VERSION 5.8 ;
BUSBITCHARS "[]" ;
DIVIDERCHAR "/" ;
UNITS
    DATABASE MICRONS 1000 ;
END UNITS

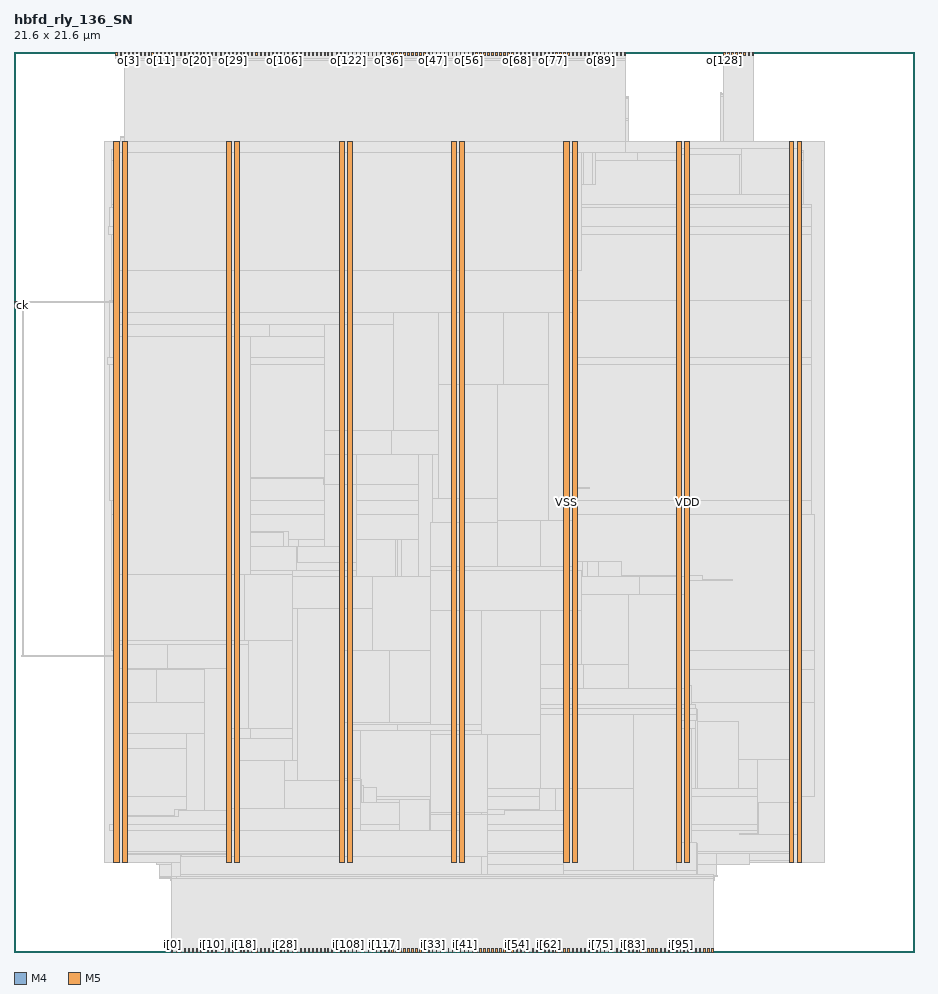
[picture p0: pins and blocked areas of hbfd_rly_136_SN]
MACRO hbfd_rly_136_SN
  FOREIGN hbfd_rly_136_SN 0 0 ;
  CLASS BLOCK ;
  SIZE 21.6 BY 21.6 ;
  PIN ck
    DIRECTION INPUT ;
    USE SIGNAL ;
    PORT
      LAYER M4 ;
        RECT  0 15.504 0.084 15.528 ;
    END
  END ck
  PIN i[0]
    DIRECTION INPUT ;
    USE SIGNAL ;
    PORT
      LAYER M5 ;
        RECT  3.792 0 3.816 0.084 ;
    END
  END i[0]
  PIN i[100]
    DIRECTION INPUT ;
    USE SIGNAL ;
    PORT
      LAYER M5 ;
        RECT  7.248 0 7.272 0.084 ;
    END
  END i[100]
  PIN i[101]
    DIRECTION INPUT ;
    USE SIGNAL ;
    PORT
      LAYER M5 ;
        RECT  7.344 0 7.368 0.084 ;
    END
  END i[101]
  PIN i[102]
    DIRECTION INPUT ;
    USE SIGNAL ;
    PORT
      LAYER M5 ;
        RECT  7.44 0 7.464 0.084 ;
    END
  END i[102]
  PIN i[103]
    DIRECTION INPUT ;
    USE SIGNAL ;
    PORT
      LAYER M5 ;
        RECT  7.536 0 7.56 0.084 ;
    END
  END i[103]
  PIN i[104]
    DIRECTION INPUT ;
    USE SIGNAL ;
    PORT
      LAYER M5 ;
        RECT  7.632 0 7.656 0.084 ;
    END
  END i[104]
  PIN i[105]
    DIRECTION INPUT ;
    USE SIGNAL ;
    PORT
      LAYER M5 ;
        RECT  7.728 0 7.752 0.084 ;
    END
  END i[105]
  PIN i[106]
    DIRECTION INPUT ;
    USE SIGNAL ;
    PORT
      LAYER M5 ;
        RECT  7.824 0 7.848 0.084 ;
    END
  END i[106]
  PIN i[107]
    DIRECTION INPUT ;
    USE SIGNAL ;
    PORT
      LAYER M5 ;
        RECT  7.92 0 7.944 0.084 ;
    END
  END i[107]
  PIN i[108]
    DIRECTION INPUT ;
    USE SIGNAL ;
    PORT
      LAYER M5 ;
        RECT  8.016 0 8.04 0.084 ;
    END
  END i[108]
  PIN i[109]
    DIRECTION INPUT ;
    USE SIGNAL ;
    PORT
      LAYER M5 ;
        RECT  8.112 0 8.136 0.084 ;
    END
  END i[109]
  PIN i[10]
    DIRECTION INPUT ;
    USE SIGNAL ;
    PORT
      LAYER M5 ;
        RECT  4.752 0 4.776 0.084 ;
    END
  END i[10]
  PIN i[110]
    DIRECTION INPUT ;
    USE SIGNAL ;
    PORT
      LAYER M5 ;
        RECT  8.208 0 8.232 0.084 ;
    END
  END i[110]
  PIN i[111]
    DIRECTION INPUT ;
    USE SIGNAL ;
    PORT
      LAYER M5 ;
        RECT  8.304 0 8.328 0.084 ;
    END
  END i[111]
  PIN i[112]
    DIRECTION INPUT ;
    USE SIGNAL ;
    PORT
      LAYER M5 ;
        RECT  8.4 0 8.424 0.084 ;
    END
  END i[112]
  PIN i[113]
    DIRECTION INPUT ;
    USE SIGNAL ;
    PORT
      LAYER M5 ;
        RECT  8.496 0 8.52 0.084 ;
    END
  END i[113]
  PIN i[114]
    DIRECTION INPUT ;
    USE SIGNAL ;
    PORT
      LAYER M5 ;
        RECT  8.592 0 8.616 0.084 ;
    END
  END i[114]
  PIN i[115]
    DIRECTION INPUT ;
    USE SIGNAL ;
    PORT
      LAYER M5 ;
        RECT  8.688 0 8.712 0.084 ;
    END
  END i[115]
  PIN i[116]
    DIRECTION INPUT ;
    USE SIGNAL ;
    PORT
      LAYER M5 ;
        RECT  8.784 0 8.808 0.084 ;
    END
  END i[116]
  PIN i[117]
    DIRECTION INPUT ;
    USE SIGNAL ;
    PORT
      LAYER M5 ;
        RECT  8.88 0 8.904 0.084 ;
    END
  END i[117]
  PIN i[118]
    DIRECTION INPUT ;
    USE SIGNAL ;
    PORT
      LAYER M5 ;
        RECT  8.976 0 9 0.084 ;
    END
  END i[118]
  PIN i[119]
    DIRECTION INPUT ;
    USE SIGNAL ;
    PORT
      LAYER M5 ;
        RECT  9.072 0 9.096 0.084 ;
    END
  END i[119]
  PIN i[11]
    DIRECTION INPUT ;
    USE SIGNAL ;
    PORT
      LAYER M5 ;
        RECT  4.848 0 4.872 0.084 ;
    END
  END i[11]
  PIN i[120]
    DIRECTION INPUT ;
    USE SIGNAL ;
    PORT
      LAYER M5 ;
        RECT  9.168 0 9.192 0.084 ;
    END
  END i[120]
  PIN i[121]
    DIRECTION INPUT ;
    USE SIGNAL ;
    PORT
      LAYER M5 ;
        RECT  9.264 0 9.288 0.084 ;
    END
  END i[121]
  PIN i[122]
    DIRECTION INPUT ;
    USE SIGNAL ;
    PORT
      LAYER M5 ;
        RECT  9.36 0 9.384 0.084 ;
    END
  END i[122]
  PIN i[123]
    DIRECTION INPUT ;
    USE SIGNAL ;
    PORT
      LAYER M5 ;
        RECT  9.456 0 9.48 0.084 ;
    END
  END i[123]
  PIN i[124]
    DIRECTION INPUT ;
    USE SIGNAL ;
    PORT
      LAYER M5 ;
        RECT  9.552 0 9.576 0.084 ;
    END
  END i[124]
  PIN i[125]
    DIRECTION INPUT ;
    USE SIGNAL ;
    PORT
      LAYER M5 ;
        RECT  9.648 0 9.672 0.084 ;
    END
  END i[125]
  PIN i[126]
    DIRECTION INPUT ;
    USE SIGNAL ;
    PORT
      LAYER M5 ;
        RECT  9.744 0 9.768 0.084 ;
    END
  END i[126]
  PIN i[127]
    DIRECTION INPUT ;
    USE SIGNAL ;
    PORT
      LAYER M5 ;
        RECT  9.84 0 9.864 0.084 ;
    END
  END i[127]
  PIN i[128]
    DIRECTION INPUT ;
    USE SIGNAL ;
    PORT
      LAYER M5 ;
        RECT  16.08 0 16.104 0.084 ;
    END
  END i[128]
  PIN i[129]
    DIRECTION INPUT ;
    USE SIGNAL ;
    PORT
      LAYER M5 ;
        RECT  16.176 0 16.2 0.084 ;
    END
  END i[129]
  PIN i[12]
    DIRECTION INPUT ;
    USE SIGNAL ;
    PORT
      LAYER M5 ;
        RECT  4.944 0 4.968 0.084 ;
    END
  END i[12]
  PIN i[130]
    DIRECTION INPUT ;
    USE SIGNAL ;
    PORT
      LAYER M5 ;
        RECT  16.272 0 16.296 0.084 ;
    END
  END i[130]
  PIN i[131]
    DIRECTION INPUT ;
    USE SIGNAL ;
    PORT
      LAYER M5 ;
        RECT  16.368 0 16.392 0.084 ;
    END
  END i[131]
  PIN i[132]
    DIRECTION INPUT ;
    USE SIGNAL ;
    PORT
      LAYER M5 ;
        RECT  16.464 0 16.488 0.084 ;
    END
  END i[132]
  PIN i[133]
    DIRECTION INPUT ;
    USE SIGNAL ;
    PORT
      LAYER M5 ;
        RECT  16.56 0 16.584 0.084 ;
    END
  END i[133]
  PIN i[134]
    DIRECTION INPUT ;
    USE SIGNAL ;
    PORT
      LAYER M5 ;
        RECT  16.656 0 16.68 0.084 ;
    END
  END i[134]
  PIN i[135]
    DIRECTION INPUT ;
    USE SIGNAL ;
    PORT
      LAYER M5 ;
        RECT  16.752 0 16.776 0.084 ;
    END
  END i[135]
  PIN i[13]
    DIRECTION INPUT ;
    USE SIGNAL ;
    PORT
      LAYER M5 ;
        RECT  5.04 0 5.064 0.084 ;
    END
  END i[13]
  PIN i[14]
    DIRECTION INPUT ;
    USE SIGNAL ;
    PORT
      LAYER M5 ;
        RECT  5.136 0 5.16 0.084 ;
    END
  END i[14]
  PIN i[15]
    DIRECTION INPUT ;
    USE SIGNAL ;
    PORT
      LAYER M5 ;
        RECT  5.232 0 5.256 0.084 ;
    END
  END i[15]
  PIN i[16]
    DIRECTION INPUT ;
    USE SIGNAL ;
    PORT
      LAYER M5 ;
        RECT  5.328 0 5.352 0.084 ;
    END
  END i[16]
  PIN i[17]
    DIRECTION INPUT ;
    USE SIGNAL ;
    PORT
      LAYER M5 ;
        RECT  5.424 0 5.448 0.084 ;
    END
  END i[17]
  PIN i[18]
    DIRECTION INPUT ;
    USE SIGNAL ;
    PORT
      LAYER M5 ;
        RECT  5.52 0 5.544 0.084 ;
    END
  END i[18]
  PIN i[19]
    DIRECTION INPUT ;
    USE SIGNAL ;
    PORT
      LAYER M5 ;
        RECT  5.616 0 5.64 0.084 ;
    END
  END i[19]
  PIN i[1]
    DIRECTION INPUT ;
    USE SIGNAL ;
    PORT
      LAYER M5 ;
        RECT  3.888 0 3.912 0.084 ;
    END
  END i[1]
  PIN i[20]
    DIRECTION INPUT ;
    USE SIGNAL ;
    PORT
      LAYER M5 ;
        RECT  5.712 0 5.736 0.084 ;
    END
  END i[20]
  PIN i[21]
    DIRECTION INPUT ;
    USE SIGNAL ;
    PORT
      LAYER M5 ;
        RECT  5.808 0 5.832 0.084 ;
    END
  END i[21]
  PIN i[22]
    DIRECTION INPUT ;
    USE SIGNAL ;
    PORT
      LAYER M5 ;
        RECT  5.904 0 5.928 0.084 ;
    END
  END i[22]
  PIN i[23]
    DIRECTION INPUT ;
    USE SIGNAL ;
    PORT
      LAYER M5 ;
        RECT  6 0 6.024 0.084 ;
    END
  END i[23]
  PIN i[24]
    DIRECTION INPUT ;
    USE SIGNAL ;
    PORT
      LAYER M5 ;
        RECT  6.096 0 6.12 0.084 ;
    END
  END i[24]
  PIN i[25]
    DIRECTION INPUT ;
    USE SIGNAL ;
    PORT
      LAYER M5 ;
        RECT  6.192 0 6.216 0.084 ;
    END
  END i[25]
  PIN i[26]
    DIRECTION INPUT ;
    USE SIGNAL ;
    PORT
      LAYER M5 ;
        RECT  6.288 0 6.312 0.084 ;
    END
  END i[26]
  PIN i[27]
    DIRECTION INPUT ;
    USE SIGNAL ;
    PORT
      LAYER M5 ;
        RECT  6.384 0 6.408 0.084 ;
    END
  END i[27]
  PIN i[28]
    DIRECTION INPUT ;
    USE SIGNAL ;
    PORT
      LAYER M5 ;
        RECT  6.48 0 6.504 0.084 ;
    END
  END i[28]
  PIN i[29]
    DIRECTION INPUT ;
    USE SIGNAL ;
    PORT
      LAYER M5 ;
        RECT  6.576 0 6.6 0.084 ;
    END
  END i[29]
  PIN i[2]
    DIRECTION INPUT ;
    USE SIGNAL ;
    PORT
      LAYER M5 ;
        RECT  3.984 0 4.008 0.084 ;
    END
  END i[2]
  PIN i[30]
    DIRECTION INPUT ;
    USE SIGNAL ;
    PORT
      LAYER M5 ;
        RECT  6.672 0 6.696 0.084 ;
    END
  END i[30]
  PIN i[31]
    DIRECTION INPUT ;
    USE SIGNAL ;
    PORT
      LAYER M5 ;
        RECT  6.768 0 6.792 0.084 ;
    END
  END i[31]
  PIN i[32]
    DIRECTION INPUT ;
    USE SIGNAL ;
    PORT
      LAYER M5 ;
        RECT  9.936 0 9.96 0.084 ;
    END
  END i[32]
  PIN i[33]
    DIRECTION INPUT ;
    USE SIGNAL ;
    PORT
      LAYER M5 ;
        RECT  10.032 0 10.056 0.084 ;
    END
  END i[33]
  PIN i[34]
    DIRECTION INPUT ;
    USE SIGNAL ;
    PORT
      LAYER M5 ;
        RECT  10.128 0 10.152 0.084 ;
    END
  END i[34]
  PIN i[35]
    DIRECTION INPUT ;
    USE SIGNAL ;
    PORT
      LAYER M5 ;
        RECT  10.224 0 10.248 0.084 ;
    END
  END i[35]
  PIN i[36]
    DIRECTION INPUT ;
    USE SIGNAL ;
    PORT
      LAYER M5 ;
        RECT  10.32 0 10.344 0.084 ;
    END
  END i[36]
  PIN i[37]
    DIRECTION INPUT ;
    USE SIGNAL ;
    PORT
      LAYER M5 ;
        RECT  10.416 0 10.44 0.084 ;
    END
  END i[37]
  PIN i[38]
    DIRECTION INPUT ;
    USE SIGNAL ;
    PORT
      LAYER M5 ;
        RECT  10.512 0 10.536 0.084 ;
    END
  END i[38]
  PIN i[39]
    DIRECTION INPUT ;
    USE SIGNAL ;
    PORT
      LAYER M5 ;
        RECT  10.608 0 10.632 0.084 ;
    END
  END i[39]
  PIN i[3]
    DIRECTION INPUT ;
    USE SIGNAL ;
    PORT
      LAYER M5 ;
        RECT  4.08 0 4.104 0.084 ;
    END
  END i[3]
  PIN i[40]
    DIRECTION INPUT ;
    USE SIGNAL ;
    PORT
      LAYER M5 ;
        RECT  10.704 0 10.728 0.084 ;
    END
  END i[40]
  PIN i[41]
    DIRECTION INPUT ;
    USE SIGNAL ;
    PORT
      LAYER M5 ;
        RECT  10.8 0 10.824 0.084 ;
    END
  END i[41]
  PIN i[42]
    DIRECTION INPUT ;
    USE SIGNAL ;
    PORT
      LAYER M5 ;
        RECT  10.896 0 10.92 0.084 ;
    END
  END i[42]
  PIN i[43]
    DIRECTION INPUT ;
    USE SIGNAL ;
    PORT
      LAYER M5 ;
        RECT  10.992 0 11.016 0.084 ;
    END
  END i[43]
  PIN i[44]
    DIRECTION INPUT ;
    USE SIGNAL ;
    PORT
      LAYER M5 ;
        RECT  11.088 0 11.112 0.084 ;
    END
  END i[44]
  PIN i[45]
    DIRECTION INPUT ;
    USE SIGNAL ;
    PORT
      LAYER M5 ;
        RECT  11.184 0 11.208 0.084 ;
    END
  END i[45]
  PIN i[46]
    DIRECTION INPUT ;
    USE SIGNAL ;
    PORT
      LAYER M5 ;
        RECT  11.28 0 11.304 0.084 ;
    END
  END i[46]
  PIN i[47]
    DIRECTION INPUT ;
    USE SIGNAL ;
    PORT
      LAYER M5 ;
        RECT  11.376 0 11.4 0.084 ;
    END
  END i[47]
  PIN i[48]
    DIRECTION INPUT ;
    USE SIGNAL ;
    PORT
      LAYER M5 ;
        RECT  11.472 0 11.496 0.084 ;
    END
  END i[48]
  PIN i[49]
    DIRECTION INPUT ;
    USE SIGNAL ;
    PORT
      LAYER M5 ;
        RECT  11.568 0 11.592 0.084 ;
    END
  END i[49]
  PIN i[4]
    DIRECTION INPUT ;
    USE SIGNAL ;
    PORT
      LAYER M5 ;
        RECT  4.176 0 4.2 0.084 ;
    END
  END i[4]
  PIN i[50]
    DIRECTION INPUT ;
    USE SIGNAL ;
    PORT
      LAYER M5 ;
        RECT  11.664 0 11.688 0.084 ;
    END
  END i[50]
  PIN i[51]
    DIRECTION INPUT ;
    USE SIGNAL ;
    PORT
      LAYER M5 ;
        RECT  11.76 0 11.784 0.084 ;
    END
  END i[51]
  PIN i[52]
    DIRECTION INPUT ;
    USE SIGNAL ;
    PORT
      LAYER M5 ;
        RECT  11.856 0 11.88 0.084 ;
    END
  END i[52]
  PIN i[53]
    DIRECTION INPUT ;
    USE SIGNAL ;
    PORT
      LAYER M5 ;
        RECT  11.952 0 11.976 0.084 ;
    END
  END i[53]
  PIN i[54]
    DIRECTION INPUT ;
    USE SIGNAL ;
    PORT
      LAYER M5 ;
        RECT  12.048 0 12.072 0.084 ;
    END
  END i[54]
  PIN i[55]
    DIRECTION INPUT ;
    USE SIGNAL ;
    PORT
      LAYER M5 ;
        RECT  12.144 0 12.168 0.084 ;
    END
  END i[55]
  PIN i[56]
    DIRECTION INPUT ;
    USE SIGNAL ;
    PORT
      LAYER M5 ;
        RECT  12.24 0 12.264 0.084 ;
    END
  END i[56]
  PIN i[57]
    DIRECTION INPUT ;
    USE SIGNAL ;
    PORT
      LAYER M5 ;
        RECT  12.336 0 12.36 0.084 ;
    END
  END i[57]
  PIN i[58]
    DIRECTION INPUT ;
    USE SIGNAL ;
    PORT
      LAYER M5 ;
        RECT  12.432 0 12.456 0.084 ;
    END
  END i[58]
  PIN i[59]
    DIRECTION INPUT ;
    USE SIGNAL ;
    PORT
      LAYER M5 ;
        RECT  12.528 0 12.552 0.084 ;
    END
  END i[59]
  PIN i[5]
    DIRECTION INPUT ;
    USE SIGNAL ;
    PORT
      LAYER M5 ;
        RECT  4.272 0 4.296 0.084 ;
    END
  END i[5]
  PIN i[60]
    DIRECTION INPUT ;
    USE SIGNAL ;
    PORT
      LAYER M5 ;
        RECT  12.624 0 12.648 0.084 ;
    END
  END i[60]
  PIN i[61]
    DIRECTION INPUT ;
    USE SIGNAL ;
    PORT
      LAYER M5 ;
        RECT  12.72 0 12.744 0.084 ;
    END
  END i[61]
  PIN i[62]
    DIRECTION INPUT ;
    USE SIGNAL ;
    PORT
      LAYER M5 ;
        RECT  12.816 0 12.84 0.084 ;
    END
  END i[62]
  PIN i[63]
    DIRECTION INPUT ;
    USE SIGNAL ;
    PORT
      LAYER M5 ;
        RECT  12.912 0 12.936 0.084 ;
    END
  END i[63]
  PIN i[64]
    DIRECTION INPUT ;
    USE SIGNAL ;
    PORT
      LAYER M5 ;
        RECT  13.008 0 13.032 0.084 ;
    END
  END i[64]
  PIN i[65]
    DIRECTION INPUT ;
    USE SIGNAL ;
    PORT
      LAYER M5 ;
        RECT  13.104 0 13.128 0.084 ;
    END
  END i[65]
  PIN i[66]
    DIRECTION INPUT ;
    USE SIGNAL ;
    PORT
      LAYER M5 ;
        RECT  13.2 0 13.224 0.084 ;
    END
  END i[66]
  PIN i[67]
    DIRECTION INPUT ;
    USE SIGNAL ;
    PORT
      LAYER M5 ;
        RECT  13.296 0 13.32 0.084 ;
    END
  END i[67]
  PIN i[68]
    DIRECTION INPUT ;
    USE SIGNAL ;
    PORT
      LAYER M5 ;
        RECT  13.392 0 13.416 0.084 ;
    END
  END i[68]
  PIN i[69]
    DIRECTION INPUT ;
    USE SIGNAL ;
    PORT
      LAYER M5 ;
        RECT  13.488 0 13.512 0.084 ;
    END
  END i[69]
  PIN i[6]
    DIRECTION INPUT ;
    USE SIGNAL ;
    PORT
      LAYER M5 ;
        RECT  4.368 0 4.392 0.084 ;
    END
  END i[6]
  PIN i[70]
    DIRECTION INPUT ;
    USE SIGNAL ;
    PORT
      LAYER M5 ;
        RECT  13.584 0 13.608 0.084 ;
    END
  END i[70]
  PIN i[71]
    DIRECTION INPUT ;
    USE SIGNAL ;
    PORT
      LAYER M5 ;
        RECT  13.68 0 13.704 0.084 ;
    END
  END i[71]
  PIN i[72]
    DIRECTION INPUT ;
    USE SIGNAL ;
    PORT
      LAYER M5 ;
        RECT  13.776 0 13.8 0.084 ;
    END
  END i[72]
  PIN i[73]
    DIRECTION INPUT ;
    USE SIGNAL ;
    PORT
      LAYER M5 ;
        RECT  13.872 0 13.896 0.084 ;
    END
  END i[73]
  PIN i[74]
    DIRECTION INPUT ;
    USE SIGNAL ;
    PORT
      LAYER M5 ;
        RECT  13.968 0 13.992 0.084 ;
    END
  END i[74]
  PIN i[75]
    DIRECTION INPUT ;
    USE SIGNAL ;
    PORT
      LAYER M5 ;
        RECT  14.064 0 14.088 0.084 ;
    END
  END i[75]
  PIN i[76]
    DIRECTION INPUT ;
    USE SIGNAL ;
    PORT
      LAYER M5 ;
        RECT  14.16 0 14.184 0.084 ;
    END
  END i[76]
  PIN i[77]
    DIRECTION INPUT ;
    USE SIGNAL ;
    PORT
      LAYER M5 ;
        RECT  14.256 0 14.28 0.084 ;
    END
  END i[77]
  PIN i[78]
    DIRECTION INPUT ;
    USE SIGNAL ;
    PORT
      LAYER M5 ;
        RECT  14.352 0 14.376 0.084 ;
    END
  END i[78]
  PIN i[79]
    DIRECTION INPUT ;
    USE SIGNAL ;
    PORT
      LAYER M5 ;
        RECT  14.448 0 14.472 0.084 ;
    END
  END i[79]
  PIN i[7]
    DIRECTION INPUT ;
    USE SIGNAL ;
    PORT
      LAYER M5 ;
        RECT  4.464 0 4.488 0.084 ;
    END
  END i[7]
  PIN i[80]
    DIRECTION INPUT ;
    USE SIGNAL ;
    PORT
      LAYER M5 ;
        RECT  14.544 0 14.568 0.084 ;
    END
  END i[80]
  PIN i[81]
    DIRECTION INPUT ;
    USE SIGNAL ;
    PORT
      LAYER M5 ;
        RECT  14.64 0 14.664 0.084 ;
    END
  END i[81]
  PIN i[82]
    DIRECTION INPUT ;
    USE SIGNAL ;
    PORT
      LAYER M5 ;
        RECT  14.736 0 14.76 0.084 ;
    END
  END i[82]
  PIN i[83]
    DIRECTION INPUT ;
    USE SIGNAL ;
    PORT
      LAYER M5 ;
        RECT  14.832 0 14.856 0.084 ;
    END
  END i[83]
  PIN i[84]
    DIRECTION INPUT ;
    USE SIGNAL ;
    PORT
      LAYER M5 ;
        RECT  14.928 0 14.952 0.084 ;
    END
  END i[84]
  PIN i[85]
    DIRECTION INPUT ;
    USE SIGNAL ;
    PORT
      LAYER M5 ;
        RECT  15.024 0 15.048 0.084 ;
    END
  END i[85]
  PIN i[86]
    DIRECTION INPUT ;
    USE SIGNAL ;
    PORT
      LAYER M5 ;
        RECT  15.12 0 15.144 0.084 ;
    END
  END i[86]
  PIN i[87]
    DIRECTION INPUT ;
    USE SIGNAL ;
    PORT
      LAYER M5 ;
        RECT  15.216 0 15.24 0.084 ;
    END
  END i[87]
  PIN i[88]
    DIRECTION INPUT ;
    USE SIGNAL ;
    PORT
      LAYER M5 ;
        RECT  15.312 0 15.336 0.084 ;
    END
  END i[88]
  PIN i[89]
    DIRECTION INPUT ;
    USE SIGNAL ;
    PORT
      LAYER M5 ;
        RECT  15.408 0 15.432 0.084 ;
    END
  END i[89]
  PIN i[8]
    DIRECTION INPUT ;
    USE SIGNAL ;
    PORT
      LAYER M5 ;
        RECT  4.56 0 4.584 0.084 ;
    END
  END i[8]
  PIN i[90]
    DIRECTION INPUT ;
    USE SIGNAL ;
    PORT
      LAYER M5 ;
        RECT  15.504 0 15.528 0.084 ;
    END
  END i[90]
  PIN i[91]
    DIRECTION INPUT ;
    USE SIGNAL ;
    PORT
      LAYER M5 ;
        RECT  15.6 0 15.624 0.084 ;
    END
  END i[91]
  PIN i[92]
    DIRECTION INPUT ;
    USE SIGNAL ;
    PORT
      LAYER M5 ;
        RECT  15.696 0 15.72 0.084 ;
    END
  END i[92]
  PIN i[93]
    DIRECTION INPUT ;
    USE SIGNAL ;
    PORT
      LAYER M5 ;
        RECT  15.792 0 15.816 0.084 ;
    END
  END i[93]
  PIN i[94]
    DIRECTION INPUT ;
    USE SIGNAL ;
    PORT
      LAYER M5 ;
        RECT  15.888 0 15.912 0.084 ;
    END
  END i[94]
  PIN i[95]
    DIRECTION INPUT ;
    USE SIGNAL ;
    PORT
      LAYER M5 ;
        RECT  15.984 0 16.008 0.084 ;
    END
  END i[95]
  PIN i[96]
    DIRECTION INPUT ;
    USE SIGNAL ;
    PORT
      LAYER M5 ;
        RECT  6.864 0 6.888 0.084 ;
    END
  END i[96]
  PIN i[97]
    DIRECTION INPUT ;
    USE SIGNAL ;
    PORT
      LAYER M5 ;
        RECT  6.96 0 6.984 0.084 ;
    END
  END i[97]
  PIN i[98]
    DIRECTION INPUT ;
    USE SIGNAL ;
    PORT
      LAYER M5 ;
        RECT  7.056 0 7.08 0.084 ;
    END
  END i[98]
  PIN i[99]
    DIRECTION INPUT ;
    USE SIGNAL ;
    PORT
      LAYER M5 ;
        RECT  7.152 0 7.176 0.084 ;
    END
  END i[99]
  PIN i[9]
    DIRECTION INPUT ;
    USE SIGNAL ;
    PORT
      LAYER M5 ;
        RECT  4.656 0 4.68 0.084 ;
    END
  END i[9]
  PIN o[0]
    DIRECTION OUTPUT ;
    USE SIGNAL ;
    PORT
      LAYER M5 ;
        RECT  2.448 21.516 2.472 21.6 ;
    END
  END o[0]
  PIN o[100]
    DIRECTION OUTPUT ;
    USE SIGNAL ;
    PORT
      LAYER M5 ;
        RECT  5.904 21.516 5.928 21.6 ;
    END
  END o[100]
  PIN o[101]
    DIRECTION OUTPUT ;
    USE SIGNAL ;
    PORT
      LAYER M5 ;
        RECT  6 21.516 6.024 21.6 ;
    END
  END o[101]
  PIN o[102]
    DIRECTION OUTPUT ;
    USE SIGNAL ;
    PORT
      LAYER M5 ;
        RECT  6.096 21.516 6.12 21.6 ;
    END
  END o[102]
  PIN o[103]
    DIRECTION OUTPUT ;
    USE SIGNAL ;
    PORT
      LAYER M5 ;
        RECT  6.192 21.516 6.216 21.6 ;
    END
  END o[103]
  PIN o[104]
    DIRECTION OUTPUT ;
    USE SIGNAL ;
    PORT
      LAYER M5 ;
        RECT  6.288 21.516 6.312 21.6 ;
    END
  END o[104]
  PIN o[105]
    DIRECTION OUTPUT ;
    USE SIGNAL ;
    PORT
      LAYER M5 ;
        RECT  6.384 21.516 6.408 21.6 ;
    END
  END o[105]
  PIN o[106]
    DIRECTION OUTPUT ;
    USE SIGNAL ;
    PORT
      LAYER M5 ;
        RECT  6.48 21.516 6.504 21.6 ;
    END
  END o[106]
  PIN o[107]
    DIRECTION OUTPUT ;
    USE SIGNAL ;
    PORT
      LAYER M5 ;
        RECT  6.576 21.516 6.6 21.6 ;
    END
  END o[107]
  PIN o[108]
    DIRECTION OUTPUT ;
    USE SIGNAL ;
    PORT
      LAYER M5 ;
        RECT  6.672 21.516 6.696 21.6 ;
    END
  END o[108]
  PIN o[109]
    DIRECTION OUTPUT ;
    USE SIGNAL ;
    PORT
      LAYER M5 ;
        RECT  6.768 21.516 6.792 21.6 ;
    END
  END o[109]
  PIN o[10]
    DIRECTION OUTPUT ;
    USE SIGNAL ;
    PORT
      LAYER M5 ;
        RECT  3.408 21.516 3.432 21.6 ;
    END
  END o[10]
  PIN o[110]
    DIRECTION OUTPUT ;
    USE SIGNAL ;
    PORT
      LAYER M5 ;
        RECT  6.864 21.516 6.888 21.6 ;
    END
  END o[110]
  PIN o[111]
    DIRECTION OUTPUT ;
    USE SIGNAL ;
    PORT
      LAYER M5 ;
        RECT  6.96 21.516 6.984 21.6 ;
    END
  END o[111]
  PIN o[112]
    DIRECTION OUTPUT ;
    USE SIGNAL ;
    PORT
      LAYER M5 ;
        RECT  7.056 21.516 7.08 21.6 ;
    END
  END o[112]
  PIN o[113]
    DIRECTION OUTPUT ;
    USE SIGNAL ;
    PORT
      LAYER M5 ;
        RECT  7.152 21.516 7.176 21.6 ;
    END
  END o[113]
  PIN o[114]
    DIRECTION OUTPUT ;
    USE SIGNAL ;
    PORT
      LAYER M5 ;
        RECT  7.248 21.516 7.272 21.6 ;
    END
  END o[114]
  PIN o[115]
    DIRECTION OUTPUT ;
    USE SIGNAL ;
    PORT
      LAYER M5 ;
        RECT  7.344 21.516 7.368 21.6 ;
    END
  END o[115]
  PIN o[116]
    DIRECTION OUTPUT ;
    USE SIGNAL ;
    PORT
      LAYER M5 ;
        RECT  7.44 21.516 7.464 21.6 ;
    END
  END o[116]
  PIN o[117]
    DIRECTION OUTPUT ;
    USE SIGNAL ;
    PORT
      LAYER M5 ;
        RECT  7.536 21.516 7.56 21.6 ;
    END
  END o[117]
  PIN o[118]
    DIRECTION OUTPUT ;
    USE SIGNAL ;
    PORT
      LAYER M5 ;
        RECT  7.632 21.516 7.656 21.6 ;
    END
  END o[118]
  PIN o[119]
    DIRECTION OUTPUT ;
    USE SIGNAL ;
    PORT
      LAYER M5 ;
        RECT  7.728 21.516 7.752 21.6 ;
    END
  END o[119]
  PIN o[11]
    DIRECTION OUTPUT ;
    USE SIGNAL ;
    PORT
      LAYER M5 ;
        RECT  3.504 21.516 3.528 21.6 ;
    END
  END o[11]
  PIN o[120]
    DIRECTION OUTPUT ;
    USE SIGNAL ;
    PORT
      LAYER M5 ;
        RECT  7.824 21.516 7.848 21.6 ;
    END
  END o[120]
  PIN o[121]
    DIRECTION OUTPUT ;
    USE SIGNAL ;
    PORT
      LAYER M5 ;
        RECT  7.92 21.516 7.944 21.6 ;
    END
  END o[121]
  PIN o[122]
    DIRECTION OUTPUT ;
    USE SIGNAL ;
    PORT
      LAYER M5 ;
        RECT  8.016 21.516 8.04 21.6 ;
    END
  END o[122]
  PIN o[123]
    DIRECTION OUTPUT ;
    USE SIGNAL ;
    PORT
      LAYER M5 ;
        RECT  8.112 21.516 8.136 21.6 ;
    END
  END o[123]
  PIN o[124]
    DIRECTION OUTPUT ;
    USE SIGNAL ;
    PORT
      LAYER M5 ;
        RECT  8.208 21.516 8.232 21.6 ;
    END
  END o[124]
  PIN o[125]
    DIRECTION OUTPUT ;
    USE SIGNAL ;
    PORT
      LAYER M5 ;
        RECT  8.304 21.516 8.328 21.6 ;
    END
  END o[125]
  PIN o[126]
    DIRECTION OUTPUT ;
    USE SIGNAL ;
    PORT
      LAYER M5 ;
        RECT  8.4 21.516 8.424 21.6 ;
    END
  END o[126]
  PIN o[127]
    DIRECTION OUTPUT ;
    USE SIGNAL ;
    PORT
      LAYER M5 ;
        RECT  8.496 21.516 8.52 21.6 ;
    END
  END o[127]
  PIN o[128]
    DIRECTION OUTPUT ;
    USE SIGNAL ;
    PORT
      LAYER M5 ;
        RECT  17.04 21.516 17.064 21.6 ;
    END
  END o[128]
  PIN o[129]
    DIRECTION OUTPUT ;
    USE SIGNAL ;
    PORT
      LAYER M5 ;
        RECT  17.136 21.516 17.16 21.6 ;
    END
  END o[129]
  PIN o[12]
    DIRECTION OUTPUT ;
    USE SIGNAL ;
    PORT
      LAYER M5 ;
        RECT  3.6 21.516 3.624 21.6 ;
    END
  END o[12]
  PIN o[130]
    DIRECTION OUTPUT ;
    USE SIGNAL ;
    PORT
      LAYER M5 ;
        RECT  17.232 21.516 17.256 21.6 ;
    END
  END o[130]
  PIN o[131]
    DIRECTION OUTPUT ;
    USE SIGNAL ;
    PORT
      LAYER M5 ;
        RECT  17.328 21.516 17.352 21.6 ;
    END
  END o[131]
  PIN o[132]
    DIRECTION OUTPUT ;
    USE SIGNAL ;
    PORT
      LAYER M5 ;
        RECT  17.424 21.516 17.448 21.6 ;
    END
  END o[132]
  PIN o[133]
    DIRECTION OUTPUT ;
    USE SIGNAL ;
    PORT
      LAYER M5 ;
        RECT  17.52 21.516 17.544 21.6 ;
    END
  END o[133]
  PIN o[134]
    DIRECTION OUTPUT ;
    USE SIGNAL ;
    PORT
      LAYER M5 ;
        RECT  17.616 21.516 17.64 21.6 ;
    END
  END o[134]
  PIN o[135]
    DIRECTION OUTPUT ;
    USE SIGNAL ;
    PORT
      LAYER M5 ;
        RECT  17.712 21.516 17.736 21.6 ;
    END
  END o[135]
  PIN o[13]
    DIRECTION OUTPUT ;
    USE SIGNAL ;
    PORT
      LAYER M5 ;
        RECT  3.696 21.516 3.72 21.6 ;
    END
  END o[13]
  PIN o[14]
    DIRECTION OUTPUT ;
    USE SIGNAL ;
    PORT
      LAYER M5 ;
        RECT  3.792 21.516 3.816 21.6 ;
    END
  END o[14]
  PIN o[15]
    DIRECTION OUTPUT ;
    USE SIGNAL ;
    PORT
      LAYER M5 ;
        RECT  3.888 21.516 3.912 21.6 ;
    END
  END o[15]
  PIN o[16]
    DIRECTION OUTPUT ;
    USE SIGNAL ;
    PORT
      LAYER M5 ;
        RECT  3.984 21.516 4.008 21.6 ;
    END
  END o[16]
  PIN o[17]
    DIRECTION OUTPUT ;
    USE SIGNAL ;
    PORT
      LAYER M5 ;
        RECT  4.08 21.516 4.104 21.6 ;
    END
  END o[17]
  PIN o[18]
    DIRECTION OUTPUT ;
    USE SIGNAL ;
    PORT
      LAYER M5 ;
        RECT  4.176 21.516 4.2 21.6 ;
    END
  END o[18]
  PIN o[19]
    DIRECTION OUTPUT ;
    USE SIGNAL ;
    PORT
      LAYER M5 ;
        RECT  4.272 21.516 4.296 21.6 ;
    END
  END o[19]
  PIN o[1]
    DIRECTION OUTPUT ;
    USE SIGNAL ;
    PORT
      LAYER M5 ;
        RECT  2.544 21.516 2.568 21.6 ;
    END
  END o[1]
  PIN o[20]
    DIRECTION OUTPUT ;
    USE SIGNAL ;
    PORT
      LAYER M5 ;
        RECT  4.368 21.516 4.392 21.6 ;
    END
  END o[20]
  PIN o[21]
    DIRECTION OUTPUT ;
    USE SIGNAL ;
    PORT
      LAYER M5 ;
        RECT  4.464 21.516 4.488 21.6 ;
    END
  END o[21]
  PIN o[22]
    DIRECTION OUTPUT ;
    USE SIGNAL ;
    PORT
      LAYER M5 ;
        RECT  4.56 21.516 4.584 21.6 ;
    END
  END o[22]
  PIN o[23]
    DIRECTION OUTPUT ;
    USE SIGNAL ;
    PORT
      LAYER M5 ;
        RECT  4.656 21.516 4.68 21.6 ;
    END
  END o[23]
  PIN o[24]
    DIRECTION OUTPUT ;
    USE SIGNAL ;
    PORT
      LAYER M5 ;
        RECT  4.752 21.516 4.776 21.6 ;
    END
  END o[24]
  PIN o[25]
    DIRECTION OUTPUT ;
    USE SIGNAL ;
    PORT
      LAYER M5 ;
        RECT  4.848 21.516 4.872 21.6 ;
    END
  END o[25]
  PIN o[26]
    DIRECTION OUTPUT ;
    USE SIGNAL ;
    PORT
      LAYER M5 ;
        RECT  4.944 21.516 4.968 21.6 ;
    END
  END o[26]
  PIN o[27]
    DIRECTION OUTPUT ;
    USE SIGNAL ;
    PORT
      LAYER M5 ;
        RECT  5.04 21.516 5.064 21.6 ;
    END
  END o[27]
  PIN o[28]
    DIRECTION OUTPUT ;
    USE SIGNAL ;
    PORT
      LAYER M5 ;
        RECT  5.136 21.516 5.16 21.6 ;
    END
  END o[28]
  PIN o[29]
    DIRECTION OUTPUT ;
    USE SIGNAL ;
    PORT
      LAYER M5 ;
        RECT  5.232 21.516 5.256 21.6 ;
    END
  END o[29]
  PIN o[2]
    DIRECTION OUTPUT ;
    USE SIGNAL ;
    PORT
      LAYER M5 ;
        RECT  2.64 21.516 2.664 21.6 ;
    END
  END o[2]
  PIN o[30]
    DIRECTION OUTPUT ;
    USE SIGNAL ;
    PORT
      LAYER M5 ;
        RECT  5.328 21.516 5.352 21.6 ;
    END
  END o[30]
  PIN o[31]
    DIRECTION OUTPUT ;
    USE SIGNAL ;
    PORT
      LAYER M5 ;
        RECT  5.424 21.516 5.448 21.6 ;
    END
  END o[31]
  PIN o[32]
    DIRECTION OUTPUT ;
    USE SIGNAL ;
    PORT
      LAYER M5 ;
        RECT  8.592 21.516 8.616 21.6 ;
    END
  END o[32]
  PIN o[33]
    DIRECTION OUTPUT ;
    USE SIGNAL ;
    PORT
      LAYER M5 ;
        RECT  8.688 21.516 8.712 21.6 ;
    END
  END o[33]
  PIN o[34]
    DIRECTION OUTPUT ;
    USE SIGNAL ;
    PORT
      LAYER M5 ;
        RECT  8.784 21.516 8.808 21.6 ;
    END
  END o[34]
  PIN o[35]
    DIRECTION OUTPUT ;
    USE SIGNAL ;
    PORT
      LAYER M5 ;
        RECT  8.88 21.516 8.904 21.6 ;
    END
  END o[35]
  PIN o[36]
    DIRECTION OUTPUT ;
    USE SIGNAL ;
    PORT
      LAYER M5 ;
        RECT  8.976 21.516 9 21.6 ;
    END
  END o[36]
  PIN o[37]
    DIRECTION OUTPUT ;
    USE SIGNAL ;
    PORT
      LAYER M5 ;
        RECT  9.072 21.516 9.096 21.6 ;
    END
  END o[37]
  PIN o[38]
    DIRECTION OUTPUT ;
    USE SIGNAL ;
    PORT
      LAYER M5 ;
        RECT  9.168 21.516 9.192 21.6 ;
    END
  END o[38]
  PIN o[39]
    DIRECTION OUTPUT ;
    USE SIGNAL ;
    PORT
      LAYER M5 ;
        RECT  9.264 21.516 9.288 21.6 ;
    END
  END o[39]
  PIN o[3]
    DIRECTION OUTPUT ;
    USE SIGNAL ;
    PORT
      LAYER M5 ;
        RECT  2.736 21.516 2.76 21.6 ;
    END
  END o[3]
  PIN o[40]
    DIRECTION OUTPUT ;
    USE SIGNAL ;
    PORT
      LAYER M5 ;
        RECT  9.36 21.516 9.384 21.6 ;
    END
  END o[40]
  PIN o[41]
    DIRECTION OUTPUT ;
    USE SIGNAL ;
    PORT
      LAYER M5 ;
        RECT  9.456 21.516 9.48 21.6 ;
    END
  END o[41]
  PIN o[42]
    DIRECTION OUTPUT ;
    USE SIGNAL ;
    PORT
      LAYER M5 ;
        RECT  9.552 21.516 9.576 21.6 ;
    END
  END o[42]
  PIN o[43]
    DIRECTION OUTPUT ;
    USE SIGNAL ;
    PORT
      LAYER M5 ;
        RECT  9.648 21.516 9.672 21.6 ;
    END
  END o[43]
  PIN o[44]
    DIRECTION OUTPUT ;
    USE SIGNAL ;
    PORT
      LAYER M5 ;
        RECT  9.744 21.516 9.768 21.6 ;
    END
  END o[44]
  PIN o[45]
    DIRECTION OUTPUT ;
    USE SIGNAL ;
    PORT
      LAYER M5 ;
        RECT  9.84 21.516 9.864 21.6 ;
    END
  END o[45]
  PIN o[46]
    DIRECTION OUTPUT ;
    USE SIGNAL ;
    PORT
      LAYER M5 ;
        RECT  9.936 21.516 9.96 21.6 ;
    END
  END o[46]
  PIN o[47]
    DIRECTION OUTPUT ;
    USE SIGNAL ;
    PORT
      LAYER M5 ;
        RECT  10.032 21.516 10.056 21.6 ;
    END
  END o[47]
  PIN o[48]
    DIRECTION OUTPUT ;
    USE SIGNAL ;
    PORT
      LAYER M5 ;
        RECT  10.128 21.516 10.152 21.6 ;
    END
  END o[48]
  PIN o[49]
    DIRECTION OUTPUT ;
    USE SIGNAL ;
    PORT
      LAYER M5 ;
        RECT  10.224 21.516 10.248 21.6 ;
    END
  END o[49]
  PIN o[4]
    DIRECTION OUTPUT ;
    USE SIGNAL ;
    PORT
      LAYER M5 ;
        RECT  2.832 21.516 2.856 21.6 ;
    END
  END o[4]
  PIN o[50]
    DIRECTION OUTPUT ;
    USE SIGNAL ;
    PORT
      LAYER M5 ;
        RECT  10.32 21.516 10.344 21.6 ;
    END
  END o[50]
  PIN o[51]
    DIRECTION OUTPUT ;
    USE SIGNAL ;
    PORT
      LAYER M5 ;
        RECT  10.416 21.516 10.44 21.6 ;
    END
  END o[51]
  PIN o[52]
    DIRECTION OUTPUT ;
    USE SIGNAL ;
    PORT
      LAYER M5 ;
        RECT  10.512 21.516 10.536 21.6 ;
    END
  END o[52]
  PIN o[53]
    DIRECTION OUTPUT ;
    USE SIGNAL ;
    PORT
      LAYER M5 ;
        RECT  10.608 21.516 10.632 21.6 ;
    END
  END o[53]
  PIN o[54]
    DIRECTION OUTPUT ;
    USE SIGNAL ;
    PORT
      LAYER M5 ;
        RECT  10.704 21.516 10.728 21.6 ;
    END
  END o[54]
  PIN o[55]
    DIRECTION OUTPUT ;
    USE SIGNAL ;
    PORT
      LAYER M5 ;
        RECT  10.8 21.516 10.824 21.6 ;
    END
  END o[55]
  PIN o[56]
    DIRECTION OUTPUT ;
    USE SIGNAL ;
    PORT
      LAYER M5 ;
        RECT  10.896 21.516 10.92 21.6 ;
    END
  END o[56]
  PIN o[57]
    DIRECTION OUTPUT ;
    USE SIGNAL ;
    PORT
      LAYER M5 ;
        RECT  10.992 21.516 11.016 21.6 ;
    END
  END o[57]
  PIN o[58]
    DIRECTION OUTPUT ;
    USE SIGNAL ;
    PORT
      LAYER M5 ;
        RECT  11.088 21.516 11.112 21.6 ;
    END
  END o[58]
  PIN o[59]
    DIRECTION OUTPUT ;
    USE SIGNAL ;
    PORT
      LAYER M5 ;
        RECT  11.184 21.516 11.208 21.6 ;
    END
  END o[59]
  PIN o[5]
    DIRECTION OUTPUT ;
    USE SIGNAL ;
    PORT
      LAYER M5 ;
        RECT  2.928 21.516 2.952 21.6 ;
    END
  END o[5]
  PIN o[60]
    DIRECTION OUTPUT ;
    USE SIGNAL ;
    PORT
      LAYER M5 ;
        RECT  11.28 21.516 11.304 21.6 ;
    END
  END o[60]
  PIN o[61]
    DIRECTION OUTPUT ;
    USE SIGNAL ;
    PORT
      LAYER M5 ;
        RECT  11.376 21.516 11.4 21.6 ;
    END
  END o[61]
  PIN o[62]
    DIRECTION OUTPUT ;
    USE SIGNAL ;
    PORT
      LAYER M5 ;
        RECT  11.472 21.516 11.496 21.6 ;
    END
  END o[62]
  PIN o[63]
    DIRECTION OUTPUT ;
    USE SIGNAL ;
    PORT
      LAYER M5 ;
        RECT  11.568 21.516 11.592 21.6 ;
    END
  END o[63]
  PIN o[64]
    DIRECTION OUTPUT ;
    USE SIGNAL ;
    PORT
      LAYER M5 ;
        RECT  11.664 21.516 11.688 21.6 ;
    END
  END o[64]
  PIN o[65]
    DIRECTION OUTPUT ;
    USE SIGNAL ;
    PORT
      LAYER M5 ;
        RECT  11.76 21.516 11.784 21.6 ;
    END
  END o[65]
  PIN o[66]
    DIRECTION OUTPUT ;
    USE SIGNAL ;
    PORT
      LAYER M5 ;
        RECT  11.856 21.516 11.88 21.6 ;
    END
  END o[66]
  PIN o[67]
    DIRECTION OUTPUT ;
    USE SIGNAL ;
    PORT
      LAYER M5 ;
        RECT  11.952 21.516 11.976 21.6 ;
    END
  END o[67]
  PIN o[68]
    DIRECTION OUTPUT ;
    USE SIGNAL ;
    PORT
      LAYER M5 ;
        RECT  12.048 21.516 12.072 21.6 ;
    END
  END o[68]
  PIN o[69]
    DIRECTION OUTPUT ;
    USE SIGNAL ;
    PORT
      LAYER M5 ;
        RECT  12.144 21.516 12.168 21.6 ;
    END
  END o[69]
  PIN o[6]
    DIRECTION OUTPUT ;
    USE SIGNAL ;
    PORT
      LAYER M5 ;
        RECT  3.024 21.516 3.048 21.6 ;
    END
  END o[6]
  PIN o[70]
    DIRECTION OUTPUT ;
    USE SIGNAL ;
    PORT
      LAYER M5 ;
        RECT  12.24 21.516 12.264 21.6 ;
    END
  END o[70]
  PIN o[71]
    DIRECTION OUTPUT ;
    USE SIGNAL ;
    PORT
      LAYER M5 ;
        RECT  12.336 21.516 12.36 21.6 ;
    END
  END o[71]
  PIN o[72]
    DIRECTION OUTPUT ;
    USE SIGNAL ;
    PORT
      LAYER M5 ;
        RECT  12.432 21.516 12.456 21.6 ;
    END
  END o[72]
  PIN o[73]
    DIRECTION OUTPUT ;
    USE SIGNAL ;
    PORT
      LAYER M5 ;
        RECT  12.528 21.516 12.552 21.6 ;
    END
  END o[73]
  PIN o[74]
    DIRECTION OUTPUT ;
    USE SIGNAL ;
    PORT
      LAYER M5 ;
        RECT  12.624 21.516 12.648 21.6 ;
    END
  END o[74]
  PIN o[75]
    DIRECTION OUTPUT ;
    USE SIGNAL ;
    PORT
      LAYER M5 ;
        RECT  12.72 21.516 12.744 21.6 ;
    END
  END o[75]
  PIN o[76]
    DIRECTION OUTPUT ;
    USE SIGNAL ;
    PORT
      LAYER M5 ;
        RECT  12.816 21.516 12.84 21.6 ;
    END
  END o[76]
  PIN o[77]
    DIRECTION OUTPUT ;
    USE SIGNAL ;
    PORT
      LAYER M5 ;
        RECT  12.912 21.516 12.936 21.6 ;
    END
  END o[77]
  PIN o[78]
    DIRECTION OUTPUT ;
    USE SIGNAL ;
    PORT
      LAYER M5 ;
        RECT  13.008 21.516 13.032 21.6 ;
    END
  END o[78]
  PIN o[79]
    DIRECTION OUTPUT ;
    USE SIGNAL ;
    PORT
      LAYER M5 ;
        RECT  13.104 21.516 13.128 21.6 ;
    END
  END o[79]
  PIN o[7]
    DIRECTION OUTPUT ;
    USE SIGNAL ;
    PORT
      LAYER M5 ;
        RECT  3.12 21.516 3.144 21.6 ;
    END
  END o[7]
  PIN o[80]
    DIRECTION OUTPUT ;
    USE SIGNAL ;
    PORT
      LAYER M5 ;
        RECT  13.2 21.516 13.224 21.6 ;
    END
  END o[80]
  PIN o[81]
    DIRECTION OUTPUT ;
    USE SIGNAL ;
    PORT
      LAYER M5 ;
        RECT  13.296 21.516 13.32 21.6 ;
    END
  END o[81]
  PIN o[82]
    DIRECTION OUTPUT ;
    USE SIGNAL ;
    PORT
      LAYER M5 ;
        RECT  13.392 21.516 13.416 21.6 ;
    END
  END o[82]
  PIN o[83]
    DIRECTION OUTPUT ;
    USE SIGNAL ;
    PORT
      LAYER M5 ;
        RECT  13.488 21.516 13.512 21.6 ;
    END
  END o[83]
  PIN o[84]
    DIRECTION OUTPUT ;
    USE SIGNAL ;
    PORT
      LAYER M5 ;
        RECT  13.584 21.516 13.608 21.6 ;
    END
  END o[84]
  PIN o[85]
    DIRECTION OUTPUT ;
    USE SIGNAL ;
    PORT
      LAYER M5 ;
        RECT  13.68 21.516 13.704 21.6 ;
    END
  END o[85]
  PIN o[86]
    DIRECTION OUTPUT ;
    USE SIGNAL ;
    PORT
      LAYER M5 ;
        RECT  13.776 21.516 13.8 21.6 ;
    END
  END o[86]
  PIN o[87]
    DIRECTION OUTPUT ;
    USE SIGNAL ;
    PORT
      LAYER M5 ;
        RECT  13.872 21.516 13.896 21.6 ;
    END
  END o[87]
  PIN o[88]
    DIRECTION OUTPUT ;
    USE SIGNAL ;
    PORT
      LAYER M5 ;
        RECT  13.968 21.516 13.992 21.6 ;
    END
  END o[88]
  PIN o[89]
    DIRECTION OUTPUT ;
    USE SIGNAL ;
    PORT
      LAYER M5 ;
        RECT  14.064 21.516 14.088 21.6 ;
    END
  END o[89]
  PIN o[8]
    DIRECTION OUTPUT ;
    USE SIGNAL ;
    PORT
      LAYER M5 ;
        RECT  3.216 21.516 3.24 21.6 ;
    END
  END o[8]
  PIN o[90]
    DIRECTION OUTPUT ;
    USE SIGNAL ;
    PORT
      LAYER M5 ;
        RECT  14.16 21.516 14.184 21.6 ;
    END
  END o[90]
  PIN o[91]
    DIRECTION OUTPUT ;
    USE SIGNAL ;
    PORT
      LAYER M5 ;
        RECT  14.256 21.516 14.28 21.6 ;
    END
  END o[91]
  PIN o[92]
    DIRECTION OUTPUT ;
    USE SIGNAL ;
    PORT
      LAYER M5 ;
        RECT  14.352 21.516 14.376 21.6 ;
    END
  END o[92]
  PIN o[93]
    DIRECTION OUTPUT ;
    USE SIGNAL ;
    PORT
      LAYER M5 ;
        RECT  14.448 21.516 14.472 21.6 ;
    END
  END o[93]
  PIN o[94]
    DIRECTION OUTPUT ;
    USE SIGNAL ;
    PORT
      LAYER M5 ;
        RECT  14.544 21.516 14.568 21.6 ;
    END
  END o[94]
  PIN o[95]
    DIRECTION OUTPUT ;
    USE SIGNAL ;
    PORT
      LAYER M5 ;
        RECT  14.64 21.516 14.664 21.6 ;
    END
  END o[95]
  PIN o[96]
    DIRECTION OUTPUT ;
    USE SIGNAL ;
    PORT
      LAYER M5 ;
        RECT  5.52 21.516 5.544 21.6 ;
    END
  END o[96]
  PIN o[97]
    DIRECTION OUTPUT ;
    USE SIGNAL ;
    PORT
      LAYER M5 ;
        RECT  5.616 21.516 5.64 21.6 ;
    END
  END o[97]
  PIN o[98]
    DIRECTION OUTPUT ;
    USE SIGNAL ;
    PORT
      LAYER M5 ;
        RECT  5.712 21.516 5.736 21.6 ;
    END
  END o[98]
  PIN o[99]
    DIRECTION OUTPUT ;
    USE SIGNAL ;
    PORT
      LAYER M5 ;
        RECT  5.808 21.516 5.832 21.6 ;
    END
  END o[99]
  PIN o[9]
    DIRECTION OUTPUT ;
    USE SIGNAL ;
    PORT
      LAYER M5 ;
        RECT  3.312 21.516 3.336 21.6 ;
    END
  END o[9]
  PIN rs
    DIRECTION INPUT ;
    USE SIGNAL ;
    PORT
      LAYER M4 ;
        RECT  0 15.6 0.084 15.624 ;
    END
  END rs
  PIN VDD
    DIRECTION INOUT ;
    USE POWER ;
    PORT
      LAYER M5 ;
        RECT  18.792 2.151 18.912 19.449 ;
        RECT  16.092 2.151 16.212 19.449 ;
        RECT  13.392 2.151 13.512 19.449 ;
        RECT  10.692 2.151 10.812 19.449 ;
        RECT  7.992 2.151 8.112 19.449 ;
        RECT  5.292 2.151 5.412 19.449 ;
        RECT  2.592 2.151 2.712 19.449 ;
    END
  END VDD
  PIN VSS
    DIRECTION INOUT ;
    USE GROUND ;
    PORT
      LAYER M5 ;
        RECT  18.6 2.137 18.72 19.463 ;
        RECT  15.9 2.137 16.02 19.463 ;
        RECT  13.2 2.137 13.32 19.463 ;
        RECT  10.5 2.137 10.62 19.463 ;
        RECT  7.8 2.137 7.92 19.463 ;
        RECT  5.1 2.137 5.22 19.463 ;
        RECT  2.4 2.137 2.52 19.463 ;
    END
  END VSS
  # OT_OBS_CLOSED layer=M5 d_um=1.536 added=41
  OBS
    LAYER RVTN ;
     RECT  2.16 2.16 19.44 2.295 ;
     RECT  2.16 2.565 19.44 2.835 ;
     RECT  2.16 3.105 19.44 3.375 ;
     RECT  2.16 3.645 19.44 3.915 ;
     RECT  2.16 4.185 19.44 4.455 ;
     RECT  2.16 4.725 19.44 4.995 ;
     RECT  2.16 5.265 19.44 5.535 ;
     RECT  2.16 5.805 19.44 6.075 ;
     RECT  2.16 6.345 19.44 6.615 ;
     RECT  2.16 6.885 19.44 7.155 ;
     RECT  2.16 7.425 19.44 7.695 ;
     RECT  2.16 7.965 19.44 8.235 ;
     RECT  2.16 8.505 19.44 8.775 ;
     RECT  2.16 9.045 19.44 9.315 ;
     RECT  2.16 9.585 19.44 9.855 ;
     RECT  2.16 10.125 19.44 10.395 ;
     RECT  2.16 10.665 19.44 10.935 ;
     RECT  2.16 11.205 19.44 11.475 ;
     RECT  2.16 11.745 19.44 12.015 ;
     RECT  2.16 12.285 19.44 12.555 ;
     RECT  2.16 12.825 19.44 13.095 ;
     RECT  2.16 13.365 19.44 13.635 ;
     RECT  2.16 13.905 19.44 14.175 ;
     RECT  2.16 14.445 19.44 14.715 ;
     RECT  2.16 14.985 19.44 15.255 ;
     RECT  2.16 15.525 19.44 15.795 ;
     RECT  2.16 16.065 19.44 16.335 ;
     RECT  2.16 16.605 19.44 16.875 ;
     RECT  2.16 17.145 19.44 17.415 ;
     RECT  2.16 17.685 19.44 17.955 ;
     RECT  2.16 18.225 19.44 18.495 ;
     RECT  2.16 18.765 19.44 19.035 ;
     RECT  2.16 19.305 19.44 19.44 ;
    LAYER RVTP ;
     RECT  2.16 2.295 19.44 2.565 ;
     RECT  2.16 2.835 19.44 3.105 ;
     RECT  2.16 3.375 19.44 3.645 ;
     RECT  2.16 3.915 19.44 4.185 ;
     RECT  2.16 4.455 19.44 4.725 ;
     RECT  2.16 4.995 19.44 5.265 ;
     RECT  2.16 5.535 19.44 5.805 ;
     RECT  2.16 6.075 19.44 6.345 ;
     RECT  2.16 6.615 19.44 6.885 ;
     RECT  2.16 7.155 19.44 7.425 ;
     RECT  2.16 7.695 19.44 7.965 ;
     RECT  2.16 8.235 19.44 8.505 ;
     RECT  2.16 8.775 19.44 9.045 ;
     RECT  2.16 9.315 19.44 9.585 ;
     RECT  2.16 9.855 19.44 10.125 ;
     RECT  2.16 10.395 19.44 10.665 ;
     RECT  2.16 10.935 19.44 11.205 ;
     RECT  2.16 11.475 19.44 11.745 ;
     RECT  2.16 12.015 19.44 12.285 ;
     RECT  2.16 12.555 19.44 12.825 ;
     RECT  2.16 13.095 19.44 13.365 ;
     RECT  2.16 13.635 19.44 13.905 ;
     RECT  2.16 14.175 19.44 14.445 ;
     RECT  2.16 14.715 19.44 14.985 ;
     RECT  2.16 15.255 19.44 15.525 ;
     RECT  2.16 15.795 19.44 16.065 ;
     RECT  2.16 16.335 19.44 16.605 ;
     RECT  2.16 16.875 19.44 17.145 ;
     RECT  2.16 17.415 19.44 17.685 ;
     RECT  2.16 17.955 19.44 18.225 ;
     RECT  2.16 18.495 19.44 18.765 ;
     RECT  2.16 19.035 19.44 19.305 ;
    LAYER M1 ;
     RECT  2.16 2.151 19.44 19.449 ;
    LAYER M2 ;
     RECT  2.16 2.151 3.415 19.449 ;
     RECT  3.415 2.106 4.199 19.449 ;
     RECT  4.199 2.151 7.447 19.449 ;
     RECT  7.447 2.106 8.123 19.449 ;
     RECT  14.899 1.152 14.999 1.17 ;
     RECT  8.123 2.151 16.663 19.449 ;
     RECT  16.663 2.106 17.663 19.449 ;
     RECT  17.663 2.151 19.44 19.449 ;
    LAYER M3 ;
     RECT  6.156 0.475 6.174 0.523 ;
     RECT  12.744 0.091 12.762 0.523 ;
     RECT  6.156 0.523 6.39 0.571 ;
     RECT  5.508 0.571 6.39 0.619 ;
     RECT  7.74 1.051 7.758 1.099 ;
     RECT  10.008 0.523 10.026 1.099 ;
     RECT  10.944 0.091 10.962 1.099 ;
     RECT  12.348 0.523 12.762 1.099 ;
     RECT  13.752 0.571 13.77 1.099 ;
     RECT  14.904 1.099 14.922 1.147 ;
     RECT  4.176 0.571 4.194 1.723 ;
     RECT  5.436 0.619 6.39 1.723 ;
     RECT  7.596 1.099 7.758 1.723 ;
     RECT  8.676 1.147 8.694 1.723 ;
     RECT  9.72 1.099 10.026 1.723 ;
     RECT  10.944 1.099 12.762 1.723 ;
     RECT  13.752 1.099 14.13 1.723 ;
     RECT  14.904 1.147 15.498 1.723 ;
     RECT  3.816 1.723 16.794 1.771 ;
     RECT  3.492 1.771 16.794 1.819 ;
     RECT  3.492 1.819 16.866 2.101 ;
     RECT  17.64 2.101 17.658 2.191 ;
     RECT  18.615 2.143 18.705 2.191 ;
     RECT  2.415 2.143 2.505 2.371 ;
     RECT  3.42 2.101 16.866 2.371 ;
     RECT  17.64 2.191 18.705 2.371 ;
     RECT  2.415 2.371 18.705 2.413 ;
     RECT  2.415 2.413 18.897 2.911 ;
     RECT  2.304 2.911 18.897 3.065 ;
     RECT  2.415 3.065 18.897 3.721 ;
     RECT  2.415 3.721 19.206 5.999 ;
     RECT  2.415 5.999 2.697 6.781 ;
     RECT  3.42 5.999 19.206 6.781 ;
     RECT  2.415 6.781 19.206 7.231 ;
     RECT  2.34 7.231 19.206 10.499 ;
     RECT  2.34 10.499 19.134 10.831 ;
     RECT  2.304 10.831 19.134 14.107 ;
     RECT  2.232 14.107 19.134 14.279 ;
     RECT  2.304 14.279 19.134 15.629 ;
     RECT  2.34 15.629 19.134 17.221 ;
     RECT  2.268 17.221 19.134 17.411 ;
     RECT  2.304 17.411 19.134 17.879 ;
     RECT  2.34 17.879 19.134 17.951 ;
     RECT  2.34 17.951 18.954 18.995 ;
     RECT  15.915 18.995 18.954 19.187 ;
     RECT  16.776 19.187 18.954 19.229 ;
     RECT  2.34 18.995 14.958 19.265 ;
     RECT  16.776 19.229 18.705 19.265 ;
     RECT  2.415 19.265 14.958 19.325 ;
     RECT  2.415 19.325 14.742 19.373 ;
     RECT  16.956 19.265 18.705 19.373 ;
     RECT  2.415 19.373 5.922 19.457 ;
     RECT  15.915 19.187 16.005 19.457 ;
     RECT  18.615 19.373 18.705 19.457 ;
     RECT  2.556 19.457 5.922 19.565 ;
     RECT  6.66 19.373 14.742 19.949 ;
     RECT  6.66 19.949 10.71 19.997 ;
     RECT  11.556 19.949 14.742 19.997 ;
     RECT  2.736 19.565 5.922 20.429 ;
     RECT  2.736 20.429 4.914 20.477 ;
     RECT  6.66 19.997 10.458 20.477 ;
     RECT  2.736 20.477 4.698 20.525 ;
     RECT  5.796 20.429 5.922 20.525 ;
     RECT  6.768 20.477 7.614 20.525 ;
     RECT  8.352 20.477 10.458 20.525 ;
     RECT  11.556 19.997 11.934 20.525 ;
     RECT  13.032 19.997 13.05 20.525 ;
     RECT  13.86 19.997 14.742 20.525 ;
     RECT  16.956 19.373 17.334 20.525 ;
     RECT  9.36 20.525 10.386 20.573 ;
     RECT  16.956 20.525 17.118 20.573 ;
     RECT  16.956 20.573 16.974 20.621 ;
     RECT  2.736 20.525 3.258 21.437 ;
     RECT  2.808 21.437 3.258 21.485 ;
     RECT  9.36 20.573 9.666 21.485 ;
     RECT  11.916 20.525 11.934 21.485 ;
     RECT  13.86 20.525 13.878 21.485 ;
    LAYER M4 ;
     RECT  0.06 15.504 0.227 15.624 ;
     RECT  0.181 7.104 2.408 7.128 ;
     RECT  0.227 15.6 2.408 15.624 ;
     RECT  2.408 2.148 2.512 19.452 ;
     RECT  2.437 21.456 2.533 21.48 ;
     RECT  2.512 2.418 2.545 19.452 ;
     RECT  2.545 2.418 2.704 19.56 ;
     RECT  2.704 16.512 2.812 19.56 ;
     RECT  2.812 16.512 3.025 19.368 ;
     RECT  3.025 16.512 3.089 18.264 ;
     RECT  2.533 21.408 3.109 21.48 ;
     RECT  3.109 20.4 3.269 21.48 ;
     RECT  3.089 17.664 3.745 18.264 ;
     RECT  3.481 1.776 3.761 1.8 ;
     RECT  2.704 3.264 3.841 3.288 ;
     RECT  3.089 16.512 3.905 16.536 ;
     RECT  3.761 1.728 3.949 1.8 ;
     RECT  3.841 3.264 3.953 3.432 ;
     RECT  3.269 20.4 3.971 21.432 ;
     RECT  3.949 1.728 3.973 2.28 ;
     RECT  3.905 16.416 3.989 16.536 ;
     RECT  2.704 9.792 4.025 9.816 ;
     RECT  3.973 1.728 4.097 2.328 ;
     RECT  3.953 3.408 4.129 3.432 ;
     RECT  2.704 4.896 4.129 5.256 ;
     RECT  3.745 18.24 4.165 18.264 ;
     RECT  3.025 19.296 4.165 19.368 ;
     RECT  3.971 20.4 4.165 20.52 ;
     RECT  2.704 6.816 4.237 7.224 ;
     RECT  3.877 11.376 4.357 11.4 ;
     RECT  4.057 15.984 4.453 16.008 ;
     RECT  4.129 3.408 4.561 5.256 ;
     RECT  4.237 6.816 4.561 7.992 ;
     RECT  4.453 15.36 4.933 16.008 ;
     RECT  4.097 1.728 5.108 2.28 ;
     RECT  4.561 3.408 5.108 7.992 ;
     RECT  4.357 10.08 5.108 11.4 ;
     RECT  4.933 15.216 5.108 16.008 ;
     RECT  4.273 17.088 5.108 17.112 ;
     RECT  4.165 18.24 5.108 20.52 ;
     RECT  5.108 1.728 5.221 20.52 ;
     RECT  4.165 0.576 5.317 0.6 ;
     RECT  5.221 1.728 5.404 21.336 ;
     RECT  5.404 19.296 5.509 21.336 ;
     RECT  5.404 15.984 5.555 17.112 ;
     RECT  5.404 18.24 5.617 18.264 ;
     RECT  5.509 19.296 5.645 21.432 ;
     RECT  5.645 20.4 5.699 21.432 ;
     RECT  5.317 0.576 6.145 0.648 ;
     RECT  6.145 0.48 6.181 0.648 ;
     RECT  5.404 1.728 6.181 1.896 ;
     RECT  5.404 14.784 6.329 14.808 ;
     RECT  6.181 0.48 6.362 1.896 ;
     RECT  5.555 15.984 6.401 16.584 ;
     RECT  6.362 0.528 6.419 1.896 ;
     RECT  5.404 3.36 6.437 9.096 ;
     RECT  6.437 6.24 6.469 9.096 ;
     RECT  5.404 10.08 6.469 10.104 ;
     RECT  6.437 3.36 6.515 5.16 ;
     RECT  6.469 6.24 6.581 10.104 ;
     RECT  6.515 3.36 6.611 4.056 ;
     RECT  6.611 3.36 6.757 4.008 ;
     RECT  6.581 6.24 6.833 9.912 ;
     RECT  6.661 15.072 6.833 15.384 ;
     RECT  5.645 19.296 6.853 19.368 ;
     RECT  5.699 20.448 6.853 20.52 ;
     RECT  6.419 1.728 6.973 1.896 ;
     RECT  6.973 1.728 7.117 2.232 ;
     RECT  6.401 16.56 7.405 16.584 ;
     RECT  5.404 11.376 7.429 11.4 ;
     RECT  6.419 0.528 7.475 0.552 ;
     RECT  7.405 16.464 7.477 16.584 ;
     RECT  6.757 3.312 7.573 4.008 ;
     RECT  7.477 16.464 7.573 17.064 ;
     RECT  6.853 19.296 7.573 20.52 ;
     RECT  7.117 1.728 7.585 2.28 ;
     RECT  7.573 16.368 7.649 17.064 ;
     RECT  7.573 19.296 7.657 21.432 ;
     RECT  7.585 1.056 7.808 2.28 ;
     RECT  7.573 3.312 7.808 4.104 ;
     RECT  6.515 5.136 7.808 5.16 ;
     RECT  6.833 6.384 7.808 9.912 ;
     RECT  7.429 11.232 7.808 11.4 ;
     RECT  6.833 15.36 7.808 15.384 ;
     RECT  7.649 16.368 7.808 17.112 ;
     RECT  7.657 18.576 7.808 21.432 ;
     RECT  7.808 1.056 8.104 21.432 ;
     RECT  8.104 1.056 8.147 1.8 ;
     RECT  8.104 15.984 8.165 21.432 ;
     RECT  8.104 3.6 8.339 4.152 ;
     RECT  8.339 3.6 8.381 4.008 ;
     RECT  8.165 20.496 8.387 21.432 ;
     RECT  8.165 15.984 8.533 19.416 ;
     RECT  8.104 14.208 8.561 14.808 ;
     RECT  8.381 3.6 8.705 3.96 ;
     RECT  8.533 15.984 8.993 19.368 ;
     RECT  8.993 18.816 9.101 19.368 ;
     RECT  9.101 18.912 9.145 19.368 ;
     RECT  8.993 15.984 9.157 17.688 ;
     RECT  8.104 5.52 9.164 9.912 ;
     RECT  9.164 5.424 9.205 9.912 ;
     RECT  8.705 3.6 9.241 3.672 ;
     RECT  9.205 5.328 9.289 9.912 ;
     RECT  8.387 20.496 9.349 20.52 ;
     RECT  9.157 15.936 9.413 17.688 ;
     RECT  8.147 1.152 9.457 1.8 ;
     RECT  9.413 15.36 9.497 17.688 ;
     RECT  9.349 20.496 9.677 21.48 ;
     RECT  9.457 1.152 9.692 1.848 ;
     RECT  9.289 5.568 9.709 9.912 ;
     RECT  8.104 11.232 9.709 12.552 ;
     RECT  9.241 2.88 9.961 3.672 ;
     RECT  9.692 1.104 9.971 1.848 ;
     RECT  9.971 1.728 10.069 1.848 ;
     RECT  9.961 2.832 10.069 3.672 ;
     RECT  8.561 14.208 10.261 14.232 ;
     RECT  9.145 19.296 10.261 19.368 ;
     RECT  9.677 20.496 10.261 20.568 ;
     RECT  9.709 5.568 10.285 12.552 ;
     RECT  9.497 15.936 10.349 17.688 ;
     RECT  10.069 1.728 10.508 3.672 ;
     RECT  10.285 5.136 10.508 12.552 ;
     RECT  10.261 13.632 10.508 14.232 ;
     RECT  10.349 15.936 10.508 18.264 ;
     RECT  10.261 19.296 10.508 20.568 ;
     RECT  10.508 1.728 10.547 20.568 ;
     RECT  9.997 0.528 10.643 0.552 ;
     RECT  10.547 1.728 10.804 19.992 ;
     RECT  10.804 11.76 10.865 12.552 ;
     RECT  10.804 13.536 10.865 14.808 ;
     RECT  10.804 15.936 11.053 19.992 ;
     RECT  11.053 18.864 11.081 19.992 ;
     RECT  10.804 1.728 11.219 2.28 ;
     RECT  10.865 11.76 11.225 12.504 ;
     RECT  10.865 13.536 11.233 13.704 ;
     RECT  11.219 1.728 11.42 1.848 ;
     RECT  11.225 11.76 11.441 11.784 ;
     RECT  10.865 14.784 11.477 14.808 ;
     RECT  11.233 13.536 11.549 13.656 ;
     RECT  11.053 15.936 11.549 17.784 ;
     RECT  10.933 0.096 11.603 0.12 ;
     RECT  11.545 20.448 11.629 20.52 ;
     RECT  10.804 3.312 11.765 3.432 ;
     RECT  11.549 15.984 11.773 17.784 ;
     RECT  11.629 20.448 11.837 20.472 ;
     RECT  11.549 13.632 11.909 13.656 ;
     RECT  11.905 21.456 11.989 21.48 ;
     RECT  11.081 18.864 12.188 19.368 ;
     RECT  12.188 18.864 12.265 19.416 ;
     RECT  12.265 18.24 12.284 19.416 ;
     RECT  11.42 1.104 12.337 1.848 ;
     RECT  11.773 15.984 12.517 17.064 ;
     RECT  12.337 0.528 12.613 1.848 ;
     RECT  11.765 3.408 12.613 3.432 ;
     RECT  10.804 4.896 12.613 10.296 ;
     RECT  12.613 0.096 12.773 1.848 ;
     RECT  12.517 15.36 12.805 17.064 ;
     RECT  12.284 18.24 12.805 19.992 ;
     RECT  12.613 3.408 12.997 10.344 ;
     RECT  12.773 0.144 13.208 1.848 ;
     RECT  12.997 3.408 13.208 11.16 ;
     RECT  12.805 15.36 13.208 20.52 ;
     RECT  13.208 0.144 13.504 20.52 ;
     RECT  13.504 16.368 13.565 16.584 ;
     RECT  13.565 16.368 13.619 16.392 ;
     RECT  13.504 0.144 13.637 9.384 ;
     RECT  13.637 0.144 13.667 1.896 ;
     RECT  13.504 18.432 13.669 20.52 ;
     RECT  13.637 3.408 13.753 9.384 ;
     RECT  13.504 11.136 13.817 11.16 ;
     RECT  13.669 18.432 13.889 21.48 ;
     RECT  13.889 18.432 13.961 20.52 ;
     RECT  13.753 4.416 14.033 9.384 ;
     RECT  13.961 19.2 14.357 20.52 ;
     RECT  13.667 0.24 14.435 1.896 ;
     RECT  14.033 4.56 14.573 9.384 ;
     RECT  14.357 19.2 14.681 19.368 ;
     RECT  14.681 19.248 14.717 19.368 ;
     RECT  14.435 1.104 14.725 1.896 ;
     RECT  13.753 3.408 14.725 3.432 ;
     RECT  14.357 20.496 14.753 20.52 ;
     RECT  14.717 19.248 14.825 19.32 ;
     RECT  14.725 1.104 14.933 3.432 ;
     RECT  14.933 1.104 15.443 1.944 ;
     RECT  15.443 1.152 15.553 1.944 ;
     RECT  15.553 1.728 15.908 1.944 ;
     RECT  14.933 3.408 15.908 3.432 ;
     RECT  14.573 4.56 15.908 9.048 ;
     RECT  14.825 19.296 15.908 19.32 ;
     RECT  15.908 1.728 16.012 19.452 ;
     RECT  16.012 1.728 16.204 19.182 ;
     RECT  16.204 1.728 16.265 6.408 ;
     RECT  16.265 3.936 16.355 5.928 ;
     RECT  16.265 1.728 16.403 2.616 ;
     RECT  16.355 3.936 16.409 5.832 ;
     RECT  16.204 8.928 16.517 9.048 ;
     RECT  16.403 1.728 16.805 1.848 ;
     RECT  16.805 1.824 16.877 1.848 ;
     RECT  16.204 19.152 17.075 19.176 ;
     RECT  16.945 20.592 17.084 20.616 ;
     RECT  16.517 8.928 17.237 8.952 ;
     RECT  17.084 20.544 17.267 20.616 ;
     RECT  16.409 3.936 17.381 5.544 ;
     RECT  17.305 20.496 17.389 20.52 ;
     RECT  17.413 2.832 17.845 2.856 ;
     RECT  17.381 3.936 17.845 4.632 ;
     RECT  17.845 2.832 18.608 4.632 ;
     RECT  17.413 18.192 18.608 18.216 ;
     RECT  17.477 19.296 18.608 19.368 ;
     RECT  18.608 2.148 18.712 19.452 ;
     RECT  18.712 2.418 18.904 19.182 ;
    LAYER M5 ;
     RECT  3.792 0.016 16.776 1.763 ;
     RECT  3.888 1.763 16.776 1.811 ;
     RECT  3.984 1.811 16.776 1.859 ;
     RECT  13.2 1.859 16.392 1.955 ;
     RECT  2.4 2.137 2.52 2.151 ;
     RECT  18.6 2.137 18.72 2.151 ;
     RECT  3.984 1.859 11.208 2.291 ;
     RECT  3.984 2.291 4.008 2.339 ;
     RECT  15.9 1.955 16.392 2.627 ;
     RECT  18.6 2.151 18.912 2.821 ;
     RECT  5.1 2.291 10.812 2.915 ;
     RECT  9.984 2.915 10.812 3.301 ;
     RECT  9.984 3.301 11.208 3.349 ;
     RECT  5.1 2.915 8.328 3.443 ;
     RECT  17.856 2.821 18.912 3.587 ;
     RECT  13.2 1.955 14.856 3.925 ;
     RECT  6.48 3.443 8.328 4.115 ;
     RECT  7.8 4.115 8.328 4.163 ;
     RECT  6.48 4.115 6.792 4.595 ;
     RECT  5.1 3.443 5.412 5.125 ;
     RECT  9.984 3.349 11.352 5.219 ;
     RECT  9.984 5.219 11.208 5.317 ;
     RECT  5.1 5.125 5.688 5.363 ;
     RECT  15.9 2.627 16.212 5.365 ;
     RECT  9.216 5.317 11.208 5.459 ;
     RECT  7.8 4.163 8.112 5.509 ;
     RECT  15.9 5.365 16.344 5.557 ;
     RECT  12.624 3.925 14.856 5.701 ;
     RECT  15.9 5.557 16.392 5.701 ;
     RECT  12.624 5.701 16.392 5.843 ;
     RECT  12.624 5.843 16.344 5.939 ;
     RECT  12.624 5.939 16.212 6.323 ;
     RECT  2.4 2.151 2.712 6.805 ;
     RECT  12.624 6.323 13.656 6.899 ;
     RECT  7.8 5.509 9 7.235 ;
     RECT  2.4 6.805 3.672 7.381 ;
     RECT  5.1 5.363 5.64 7.381 ;
     RECT  2.4 7.381 5.64 7.475 ;
     RECT  9.984 5.459 11.208 8.197 ;
     RECT  12.624 6.899 13.608 8.197 ;
     RECT  6.672 4.595 6.792 8.245 ;
     RECT  7.8 7.235 8.616 8.245 ;
     RECT  14.736 6.323 16.212 8.579 ;
     RECT  6.672 8.245 8.616 9.011 ;
     RECT  15.024 8.579 16.212 9.011 ;
     RECT  2.4 7.475 5.544 9.061 ;
     RECT  6.672 9.011 8.232 9.155 ;
     RECT  9.984 8.197 13.608 9.155 ;
     RECT  9.984 9.155 13.512 9.251 ;
     RECT  6.768 9.155 8.232 9.347 ;
     RECT  6.768 9.347 6.792 9.731 ;
     RECT  9.984 9.251 11.592 10.307 ;
     RECT  12.624 9.251 13.512 10.355 ;
     RECT  10.032 10.307 11.592 10.883 ;
     RECT  7.8 9.347 8.232 11.221 ;
     RECT  7.44 11.221 8.232 11.941 ;
     RECT  7.44 11.941 9.048 12.517 ;
     RECT  10.176 10.883 11.592 13.621 ;
     RECT  2.4 9.061 5.688 14.773 ;
     RECT  2.4 14.773 6.12 15.061 ;
     RECT  7.44 12.517 9.096 15.061 ;
     RECT  2.4 15.061 9.096 15.349 ;
     RECT  10.176 13.621 11.736 15.349 ;
     RECT  12.816 10.355 13.512 15.349 ;
     RECT  0.192 7.093 0.216 15.539 ;
     RECT  2.4 15.349 13.512 16.357 ;
     RECT  15.9 9.011 16.212 19.141 ;
     RECT  17.424 18.181 17.448 19.141 ;
     RECT  2.4 16.357 13.608 19.189 ;
     RECT  15.9 19.141 17.448 19.285 ;
     RECT  18.6 3.587 18.912 19.285 ;
     RECT  15.9 19.285 18.912 19.449 ;
     RECT  2.4 19.189 14.664 19.463 ;
     RECT  15.9 19.449 16.02 19.463 ;
     RECT  17.04 19.449 18.72 19.463 ;
     RECT  2.64 19.463 14.664 21.397 ;
     RECT  2.544 21.397 14.664 21.445 ;
     RECT  2.448 21.445 14.664 21.584 ;
     RECT  17.04 19.463 17.736 21.584 ;
     RECT  3.792 1.763 3.888 1.811 ;
     RECT  3.792 1.811 3.984 2.137 ;
     RECT  11.208 1.859 11.352 2.291 ;
     RECT  14.856 1.955 15.9 5.701 ;
     RECT  2.52 2.137 3.984 2.151 ;
     RECT  2.712 2.151 3.984 2.339 ;
     RECT  4.008 2.291 5.1 2.339 ;
     RECT  10.812 2.291 11.352 3.301 ;
     RECT  11.208 3.301 11.352 3.349 ;
     RECT  5.412 3.443 6.48 4.595 ;
     RECT  11.352 3.925 12.624 5.219 ;
     RECT  6.792 4.115 7.8 8.245 ;
     RECT  8.112 4.163 8.328 5.317 ;
     RECT  5.412 4.595 6.672 5.125 ;
     RECT  5.688 5.125 6.672 5.363 ;
     RECT  11.208 5.219 12.624 8.197 ;
     RECT  8.112 5.317 9.216 5.459 ;
     RECT  5.64 5.363 6.672 7.475 ;
     RECT  8.112 5.459 9.984 5.509 ;
     RECT  9 5.509 9.984 7.235 ;
     RECT  13.656 6.323 14.736 6.899 ;
     RECT  3.672 6.805 5.1 7.381 ;
     RECT  13.608 6.899 14.736 8.579 ;
     RECT  8.616 7.235 9.984 9.011 ;
     RECT  5.544 7.475 6.672 9.061 ;
     RECT  13.608 8.579 15.024 9.011 ;
     RECT  5.688 9.061 6.672 9.155 ;
     RECT  5.688 9.155 6.768 9.731 ;
     RECT  11.592 9.251 12.624 10.355 ;
     RECT  6.792 9.347 7.8 9.731 ;
     RECT  7.44 9.731 7.8 11.221 ;
     RECT  11.592 10.355 12.816 13.621 ;
     RECT  10.032 10.883 10.176 11.941 ;
     RECT  9.048 11.941 10.176 12.517 ;
     RECT  9.096 12.517 10.176 15.349 ;
     RECT  11.736 13.621 12.816 15.349 ;
     RECT  6.12 14.773 7.44 15.061 ;
     RECT  16.212 18.181 17.424 19.141 ;
     RECT  17.448 18.181 18.6 19.285 ;
     RECT  14.664 19.189 15.9 19.463 ;
     RECT  16.02 19.449 17.04 19.463 ;
  END
END hbfd_rly_136_SN
END LIBRARY
